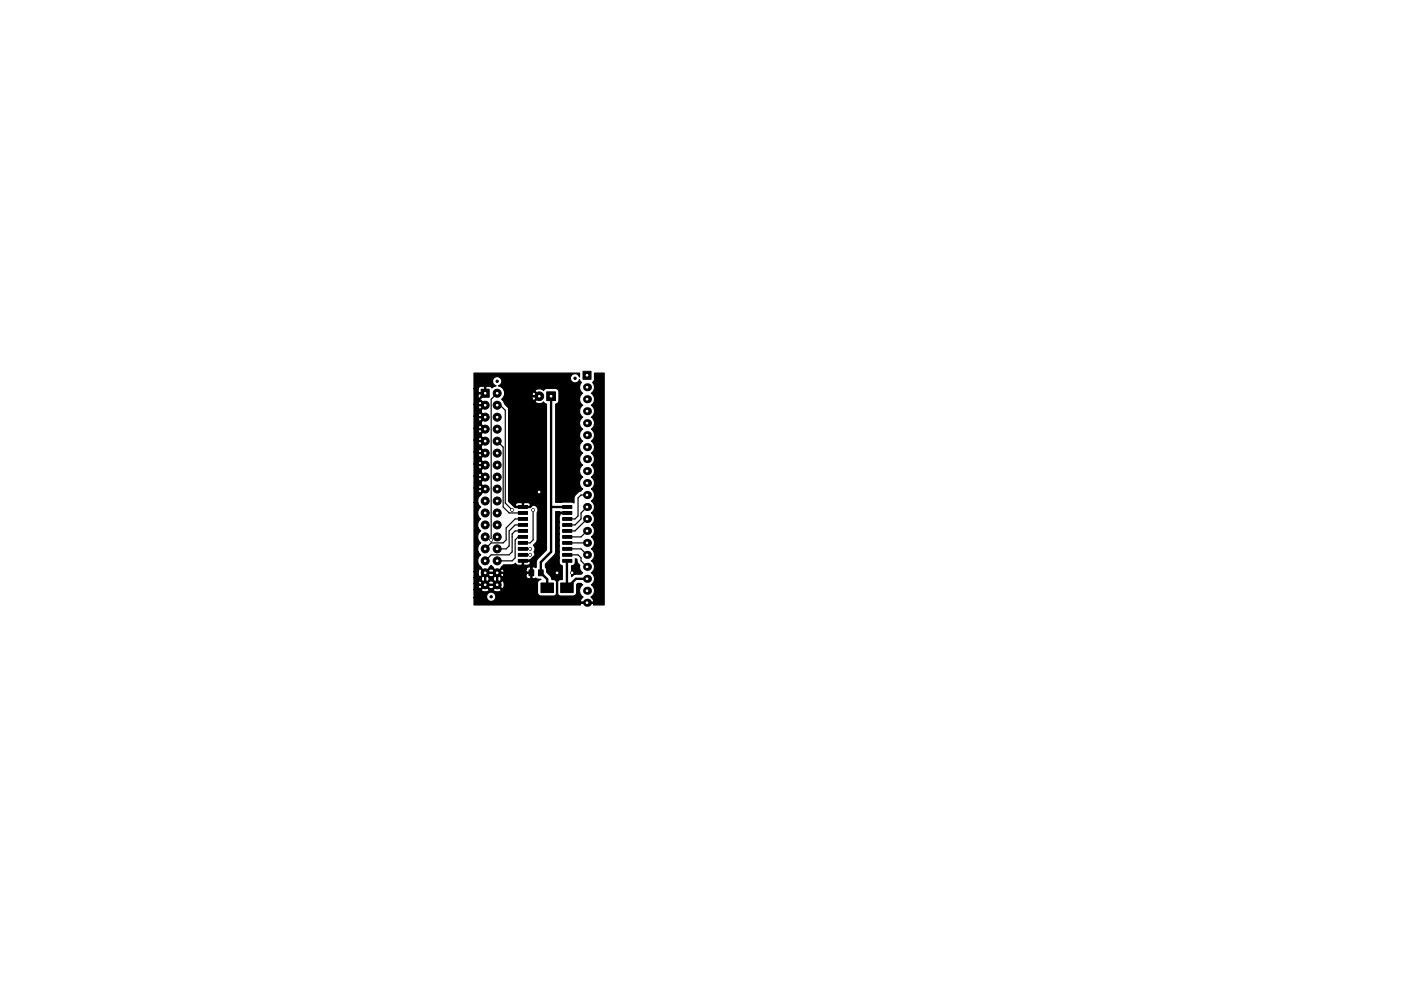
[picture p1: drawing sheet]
<svg xmlns="http://www.w3.org/2000/svg" width="297mm" height="210mm" viewBox="0 0 297 210" stroke-linecap="round" stroke-linejoin="round" font-family="sans-serif">
<g fill="#000" stroke="#000" stroke-width=".21">
<path d="M102 82.6h1.7v1.7h-1.7zM115.9 83.1h1.9v1.9h-1.9zM123.6 78.8h1.7v1.7h-1.7zM109.9 107.3h1.9v.6h-1.9zM109.9 108.5h1.9v.6h-1.9zM109.9 109.8h1.9v.6h-1.9zM109.9 111.1h1.9v.6h-1.9zM109.9 112.3h1.9v.6h-1.9zM109.9 113.6h1.9v.6h-1.9zM109.9 114.9h1.9v.6h-1.9zM109.9 116.2h1.9v.6h-1.9zM109.9 117.4h1.9v.6h-1.9z"/>
<path d="M109.9 118.7h1.9v.6h-1.9zM119.3 118.7h1.9v.6h-1.9zM119.3 117.4h1.9v.6h-1.9zM119.3 116.2h1.9v.6h-1.9zM119.3 114.9h1.9v.6h-1.9zM119.3 113.6h1.9v.6h-1.9zM119.3 112.3h1.9v.6h-1.9zM119.3 111.1h1.9v.6h-1.9zM119.3 109.8h1.9v.6h-1.9zM119.3 108.5h1.9v.6h-1.9zM119.3 107.3h1.9v.6h-1.9zM112.2 120.9h1v1.3h-1z"/>
<path d="M114.2 120.9h1v1.3h-1zM114.7 123.7h2.6v2h-2.6zM118.9 123.7h2.6v2h-2.6z"/>
<circle cx="102.9" cy="88.5" r=".85"/>
<circle cx="102.9" cy="86" r=".85"/>
<circle cx="102.9" cy="93.6" r=".85"/>
<circle cx="102.9" cy="96.1" r=".85"/>
<circle cx="102.9" cy="91.1" r=".85"/>
<circle cx="102.9" cy="98.7" r=".85"/>
<circle cx="105.4" cy="80.9" r=".25"/>
<circle cx="105.4" cy="88.5" r=".85"/>
<circle cx="105.4" cy="83.4" r=".85"/>
<circle cx="105.4" cy="96.1" r=".85"/>
<circle cx="105.4" cy="86" r=".85"/>
<circle cx="105.4" cy="93.6" r=".85"/>
<circle cx="105.4" cy="98.7" r=".85"/>
<circle cx="105.4" cy="91.1" r=".85"/>
<circle cx="114.3" cy="84.1" r=".92"/>
<circle cx="121.9" cy="80.3" r=".25"/>
<circle cx="102.9" cy="101.2" r=".85"/>
<circle cx="102.9" cy="111.4" r=".85"/>
<circle cx="102.9" cy="119" r=".85"/>
<circle cx="102.9" cy="113.9" r=".85"/>
<circle cx="102.9" cy="103.8" r=".85"/>
<circle cx="102.9" cy="106.3" r=".85"/>
<circle cx="102.9" cy="116.5" r=".85"/>
<circle cx="102.9" cy="108.8" r=".85"/>
<circle cx="104.1" cy="114.5" r=".3"/>
<circle cx="105.4" cy="113.9" r=".85"/>
<circle cx="105.4" cy="101.2" r=".85"/>
<circle cx="105.4" cy="111.4" r=".85"/>
<circle cx="105.4" cy="116.5" r=".85"/>
<circle cx="105.4" cy="119" r=".85"/>
<circle cx="105.4" cy="103.8" r=".85"/>
<circle cx="105.4" cy="106.3" r=".85"/>
<circle cx="105.4" cy="108.8" r=".85"/>
<circle cx="108.6" cy="108.2" r=".3"/>
<circle cx="112.4" cy="116.5" r=".3"/>
<circle cx="112.4" cy="117.7" r=".3"/>
<circle cx="113" cy="108.2" r=".3"/>
<circle cx="114.3" cy="104.4" r=".3"/>
<circle cx="102.9" cy="121.5" r=".85"/>
<circle cx="102.9" cy="124.1" r=".85"/>
<circle cx="104.1" cy="126.6" r=".25"/>
<circle cx="105.4" cy="121.5" r=".85"/>
<circle cx="105.4" cy="124.1" r=".85"/>
<circle cx="118.1" cy="121.5" r=".3"/>
<circle cx="121.3" cy="121.5" r=".3"/>
</g>
<g fill="#000">
<circle cx="124.5" cy="92.3" r=".85"/>
<circle cx="124.5" cy="84.7" r=".85"/>
<circle cx="124.5" cy="94.9" r=".85"/>
<circle cx="124.5" cy="82.2" r=".85"/>
<circle cx="124.5" cy="87.2" r=".85"/>
<circle cx="124.5" cy="97.4" r=".85"/>
<circle cx="124.5" cy="89.8" r=".85"/>
<circle cx="124.5" cy="99.9" r=".85"/>
<circle cx="124.5" cy="110.1" r=".85"/>
<circle cx="124.5" cy="112.6" r=".85"/>
<circle cx="124.5" cy="107.6" r=".85"/>
<circle cx="124.5" cy="115.2" r=".85"/>
<circle cx="124.5" cy="117.7" r=".85"/>
<circle cx="124.5" cy="102.5" r=".85"/>
<circle cx="124.5" cy="105" r=".85"/>
<circle cx="124.5" cy="122.8" r=".85"/>
<circle cx="124.5" cy="127.9" r=".85"/>
<circle cx="124.5" cy="120.3" r=".85"/>
<circle cx="124.5" cy="125.3" r=".85"/>
</g>
<g fill="none" stroke="#000" stroke-width=".5">
<path d="M101 98.7h1.9M101 96.1h1.9M101 93.6h1.9M101 91.1h1.9M101 88.5h1.9M101 86h1.9M102.9 83.4l-1.9 1.9v41.9l.6 .7h22.9M114.3 84l-5.1 .1-1.3 1.2v21l1.3 1.3h3.2l.6-.7h1.3v10.1l-1.9 2M116.8 84.1v33l-2.1 2.2v2.2l1.3 1.4v1.8M101 103.8h1.9M101 101.2h1.9M110.9 119h1.5"/>
<path d="M112.4 119l.3 .3v2.2h-9.8v2.6M114.3 104.4v2.5M116.8 107.6h3.5M120.3 108.8h-1.6l-.6 .7v18.4M120.3 119l-.1 5.7 1.9-1.9h2.4M105.4 121.5v2.6h-3.8l-.6-.7"/>
</g>
<g fill="none" stroke="#000" stroke-width=".25">
<path d="M105.4 83.4l-1.3 1.3v29.8M105.4 86h.6l1.1 1.1v19.6l1.5 1.5M105.4 93.6l1.3 1.3v12.7l1.2 1.2h3M110.9 110.1h-1.7l-1.9 1.9v2.5l-.6 .7h-2.6l-1.2 1.3M110.9 111.4h-1.7l-1.3 1.2v3.2l-.6 .7h-1.9M110.9 112.6h-1.7l-.6 .7v3.8l-.7 .6h-3.8l-1.2 1.3M110.9 113.9h-1l-.7 .6v3.9l-.6 .6h-3.2M110.9 116.5h1.5M110.9 117.7h1.5M113 108.2v6.3l-.6 .7h-1.5M120.3 117.7h2.3l.6 .7v.6l1.3 1.3M120.3 115.2h4.2"/>
<path d="M120.3 116.5h2.9l1.3 1.2M124.5 105h-1.3l-.6 .7v3.8l-.7 .6h-1.6M124.5 107.6l-1.3 1.2v1.3l-1.3 1.3h-1.6M124.5 110.1l-2.6 2.5h-1.6M124.5 112.6l-1.3 1.3h-2.9"/>
</g>
<path d="M100.5 79.2h22.4v.8a.99 .99 0 0 0-1.6-.5 .99 .99 0 0 0 .1 1.6 .99 .99 0 0 0 1.5-.6l.4 .6-.3 .5a1.5 1.5 0 0 0 .5 1.8 1.51 1.51 0 0 0 0 2.6 1.51 1.51 0 0 0 0 2.5 1.51 1.51 0 0 0 0 2.6 1.51 1.51 0 0 0 0 2.5 1.51 1.51 0 0 0 0 2.5 1.51 1.51 0 0 0 0 2.6 1.51 1.51 0 0 0 0 2.5 1.51 1.51 0 0 0 0 2.6l-.4 .4a2.05 2.05 0 0 0-1.4 2.5l-.5-.2-3.4 .1v-20.9l.6-.4 .1-2.2a.74 .74 0 0 0-.7-.7h-1.9l-.5 .2-.2 .3v-.2a1.18 1.18 0 0 0-1.8 .3l1.1 1.1-1.1 1.1a1.12 1.12 0 0 0 1.8 .1l.2 .2 .5 .2v31l-2.1 2.2-.2 1.5a.55 .55 0 0 0-.8 0v2.2l.5 .2 .3-.2 .3 .2 .8 .2-.5 .2-.2 .2v2.3a.74 .74 0 0 0 .7 .8h2.6l.6-.2 .2-.6v-2a.82 .82 0 0 0-1.1-.7l-.3-.8-.8-.8-.3-1.7 1.9-1.9 .3-.7v-8.6l2.6 .2v.3h-1.6l-.1 .1-.1 9.2a1.28 1.28 0 0 0 .6 1.7v3h-.3a.74 .74 0 0 0-.8 .7v2l.2 .5 .6 .3h2.6a.74 .74 0 0 0 .8-.8v-1.7l.2-.2h.7l.3 .3-.2 .1a1.54 1.54 0 0 0 .3 2.5l-.4 .4-.2 .4 .1 .3h2.7l.1-.3-.2-.4-.4-.4 .3-.2a1.54 1.54 0 0 0-.2-2.4 1.51 1.51 0 0 0 0-2.6 1.51 1.51 0 0 0 0-2.5 1.51 1.51 0 0 0 0-2.5 1.51 1.51 0 0 0 0-2.6 1.51 1.51 0 0 0 0-2.5 1.51 1.51 0 0 0 0-2.6 1.51 1.51 0 0 0 0-2.5 1.51 1.51 0 0 0 0-2.5 1.51 1.51 0 0 0 0-2.6 1.51 1.51 0 0 0 0-2.5 1.51 1.51 0 0 0 0-2.6 1.51 1.51 0 0 0 0-2.5 1.51 1.51 0 0 0 0-2.5 1.51 1.51 0 0 0 0-2.6 1.51 1.51 0 0 0 0-2.5 1.51 1.51 0 0 0 0-2.6 1.5 1.5 0 0 0 .3-2.3l.3-.3 .1-1.6h2v49.2h-2.2l-.1-.4h-2.7v.4h-22.6v-1.6h2.7l.1 .4a1 1 0 0 0 1.7 0 1 1 0 0 0-.7-1.6 1 1 0 0 0-1.1 1.2h-2.7v-1.7h1.5l.1 .3a1.1 1.1 0 0 0 1.6-.3h.8l.1 .3a1.1 1.1 0 0 0 1.7-.3l-.9-.8-.9 .8h-.8l-.8-.8-.9 .8h-1.5v-1.3h.9v.6l.2 .5h.2l.9-.8h.3l.9 .8h.5l.8-.8h.4l.9 .8h.2a1.1 1.1 0 0 0-.2-1.7l-.9 .9h-.4l-.8-.9h-.5l-.9 .9h-.3l-.9-.9-.2 .1-.2 .5h-.9v-1.2h1.5v.4l.9 .9 .8-.9v-.4h.8v.4l.9 .9 .9-.9v-.4l-.9-.9-.9 .9h-.8l-.8-.9-.9 .9h-1.5v-1.3h.9v.6l.2 .4 .2 .1 .9-.9h.3l.9 .9h.5l.8-.9h.4l.9 .9 .2-.1 .2-.5h4.6l.1 .7a.59 .59 0 0 0 .9 .1v-.9h-.8l-.2 .1h-4.6l-.2-1h4.8v.4l.2 .2h.8v-1a.6 .6 0 0 0-1 .4h-4.8l-.2-.1-.9 .8h-.4l-.8-.8h-.5l-.9 .8h-.3l-.9-.8h-.2l-.2 .6h-.9v-14.7h.8l.2 .6 .4 .4a1.57 1.57 0 0 0 0 2.5 1.57 1.57 0 0 0 0 2.5 1.57 1.57 0 0 0 0 2.6 1.57 1.57 0 0 0 0 2.5 1.57 1.57 0 0 0 .1 2.7v.1l.9 .9 1.2-1.4 1.3 1.4 1.4-1.6h1.8l.7-.3 .5 .4h.8l.1-.1v-.7h.3v.7l.2 .1h.8l.4-.2 .1-.4-.2-.2h-1.6v-.2h1.6l.1-.1a1.1 1.1 0 0 0 .9-1.8 1.01 1.01 0 0 0-.2-1.3l.5-.5 .3-.7v-5.7a1.04 1.04 0 0 0-.2-1.4 1.04 1.04 0 0 0-1.4 0l.2-.1-.1-.4-.4-.3h-.8l-.2 .2v.9h-.3v-.9l-.1-.2-1.1 .1-.2 .4 .1 .3h-.1l-.5-.2-.8-.8v-19.3l-.3-.6-.7-.8-.3-.6-.3-.4 .6-.9h5.8v.6l.2 .5 .2 .1 1-.9-1-1-.2 .1-.2 .6h-5.8a1.57 1.57 0 0 0-1.4-1.9 .99 .99 0 0 0 .6-1.6 .99 .99 0 0 0-1.6 0 .99 .99 0 0 0 .6 1.6l-.9 .4-.5-.4h-.6l-.2 .2v1.5h-1.5l-.1 .1 .1 .9 .5 .3 1.1 1.1-1.1 1v.5l1.1 1-1.1 1.1v.4l1.1 1-1.1 1.1v.4l1.1 1.1-1.1 1v.5l1.1 1-1.1 1.1v.4l1.1 1.1-1.1 1v.5l1.1 1-1.1 1.1v.4l1.1 1-1.1 1.1v.1a1.56 1.56 0 0 0-.7 1.7h-.8v-3.1h.9v.6l.2 .4 .2 .1 .9-.8-.9-.9-.2 .1-.2 .5h-.9v-2.5h.9v.6l.2 .4 .2 .1 .9-.9-.9-.9-.2 .1-.2 .6h-.9v-2.6h.9v.6l.2 .5h.2l.9-.8-.9-.9-.2 .1-.2 .5h-.9v-2.5h.9v.6l.2 .4 .2 .1 .9-.9-.9-.8h-.2l-.2 .6h-.9v-2.5h.9v.6l.2 .4 .2 .1 .9-.9-.9-.9-.2 .1-.2 .6h-.9v-2.6h.9v.6l.2 .4 .2 .1 .9-.8-.9-.9-.2 .1-.2 .5h-.9v-2.5h.9v.6l.2 .4 .2 .1 .9-.9-.9-.9-.2 .1-.2 .6h-.9v-2.6h.9v.6l.2 .5h.2l.9-.8-.9-.9-.2 .1-.2 .5h-.9v-3.2h.9v.6l.1 .2h1.2v-1.2l-.1-.2h-.7l-.5 .6h-.9zM122 118.6l.3 .1a1.2 1.2 0 0 0 .6 1.2 1.42 1.42 0 0 0 .6 1.6l-.3 .3-1.5 .1-.5 .4v-2.3a.74 .74 0 0 0 .8-.7z" fill="#000" stroke="#000" stroke-width=".25"/>
<g fill="#fff" stroke="#fff" stroke-width=".21">
<circle cx="118.1" cy="121.5" r=".17"/>
<circle cx="121.3" cy="121.5" r=".17"/>
<circle cx="114.3" cy="104.4" r=".17"/>
<circle cx="104.1" cy="114.5" r=".17"/>
<circle cx="112.4" cy="116.5" r=".17"/>
<circle cx="113" cy="108.2" r=".17"/>
<circle cx="108.6" cy="108.2" r=".17"/>
<circle cx="112.4" cy="117.7" r=".17"/>
<circle cx="124.5" cy="79.6" r=".17"/>
<circle cx="124.5" cy="82.2" r=".17"/>
<circle cx="124.5" cy="84.7" r=".17"/>
<circle cx="124.5" cy="87.2" r=".17"/>
<circle cx="124.5" cy="89.8" r=".17"/>
<circle cx="124.5" cy="92.3" r=".17"/>
<circle cx="124.5" cy="94.9" r=".17"/>
<circle cx="124.5" cy="97.4" r=".17"/>
<circle cx="124.5" cy="99.9" r=".17"/>
<circle cx="124.5" cy="102.5" r=".17"/>
<circle cx="124.5" cy="105" r=".17"/>
<circle cx="124.5" cy="107.6" r=".17"/>
<circle cx="124.5" cy="110.1" r=".17"/>
<circle cx="124.5" cy="112.6" r=".17"/>
<circle cx="124.5" cy="115.2" r=".17"/>
<circle cx="124.5" cy="117.7" r=".17"/>
<circle cx="124.5" cy="120.3" r=".17"/>
<circle cx="124.5" cy="122.8" r=".17"/>
<circle cx="124.5" cy="125.3" r=".17"/>
<circle cx="124.5" cy="127.9" r=".17"/>
<circle cx="102.9" cy="83.4" r=".17"/>
<circle cx="105.4" cy="83.4" r=".17"/>
<circle cx="102.9" cy="86" r=".17"/>
<circle cx="105.4" cy="86" r=".17"/>
<circle cx="102.9" cy="88.5" r=".17"/>
<circle cx="105.4" cy="88.5" r=".17"/>
<circle cx="102.9" cy="91.1" r=".17"/>
<circle cx="105.4" cy="91.1" r=".17"/>
<circle cx="102.9" cy="93.6" r=".17"/>
<circle cx="105.4" cy="93.6" r=".17"/>
<circle cx="102.9" cy="96.1" r=".17"/>
<circle cx="105.4" cy="96.1" r=".17"/>
<circle cx="102.9" cy="98.7" r=".17"/>
<circle cx="105.4" cy="98.7" r=".17"/>
<circle cx="102.9" cy="101.2" r=".17"/>
<circle cx="105.4" cy="101.2" r=".17"/>
<circle cx="102.9" cy="103.8" r=".17"/>
<circle cx="105.4" cy="103.8" r=".17"/>
<circle cx="102.9" cy="106.3" r=".17"/>
<circle cx="105.4" cy="106.3" r=".17"/>
<circle cx="102.9" cy="108.8" r=".17"/>
<circle cx="105.4" cy="108.8" r=".17"/>
<circle cx="102.9" cy="111.4" r=".17"/>
<circle cx="105.4" cy="111.4" r=".17"/>
<circle cx="102.9" cy="113.9" r=".17"/>
<circle cx="105.4" cy="113.9" r=".17"/>
<circle cx="102.9" cy="116.5" r=".17"/>
<circle cx="105.4" cy="116.5" r=".17"/>
<circle cx="102.9" cy="119" r=".17"/>
<circle cx="105.4" cy="119" r=".17"/>
<circle cx="102.9" cy="121.5" r=".17"/>
<circle cx="105.4" cy="121.5" r=".17"/>
<circle cx="102.9" cy="124.1" r=".17"/>
<circle cx="105.4" cy="124.1" r=".17"/>
<circle cx="116.8" cy="84.1" r=".17"/>
<circle cx="114.3" cy="84.1" r=".17"/>
</g>
</svg>
